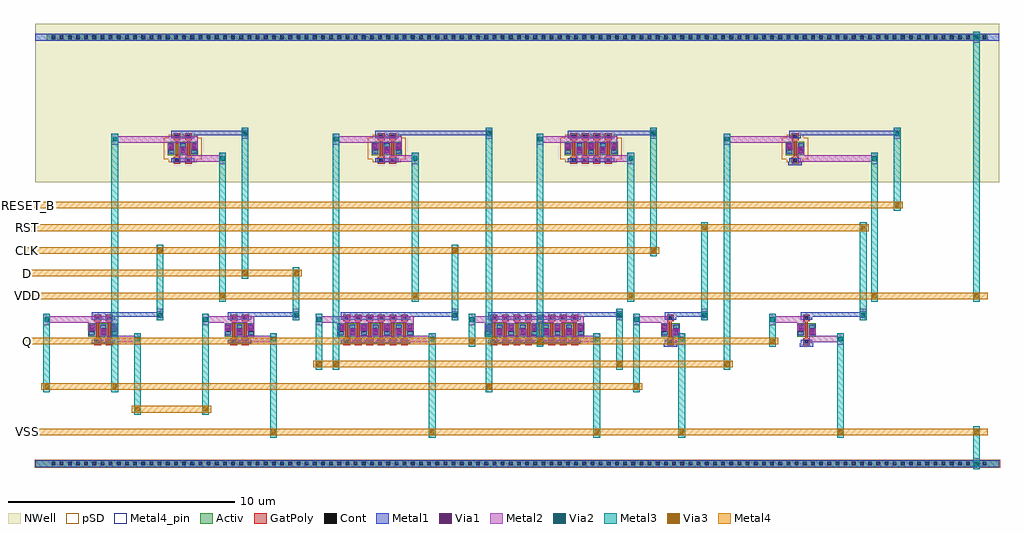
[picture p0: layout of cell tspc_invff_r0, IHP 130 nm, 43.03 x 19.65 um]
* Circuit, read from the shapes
.subckt tspc_invff_r0 CLK D Q RESET_B RST VDD VSS
XM1 dev_n_w0p6_l0p13_ng2_noguard_m1_2/D0 CLK dev_n_w0p6_l0p13_ng1_noguard_m1_7/D VSS sg13_lv_nmos w=0.6u l=0.13u m=2
XM2 VSS D dev_n_w0p6_l0p13_ng2_noguard_m1_2/D0 VSS sg13_lv_nmos w=0.6u l=0.13u m=2
XM3 VSS CLK dev_p_w0p6_l0p13_ng1_noguard_m1_8/D VSS sg13_lv_nmos w=0.6u l=0.13u m=6
XM4 VSS dev_p_w0p6_l0p13_ng1_noguard_m1_8/D Q VSS sg13_lv_nmos w=0.6u l=0.13u m=8
XM5 VSS RST dev_n_w0p6_l0p13_ng1_noguard_m1_7/D VSS sg13_lv_nmos w=0.6u l=0.13u
XM6 VSS RST Q VSS sg13_lv_nmos w=0.6u l=0.13u
XM7 VDD D dev_n_w0p6_l0p13_ng1_noguard_m1_7/D VDD sg13_lv_pmos w=0.6u l=0.13u m=2
XM8 VDD dev_n_w0p6_l0p13_ng1_noguard_m1_7/D dev_p_w0p6_l0p13_ng1_noguard_m1_8/D VDD sg13_lv_pmos w=0.6u l=0.13u m=2
XM9 VDD CLK Q VDD sg13_lv_pmos w=0.6u l=0.13u m=4
XM10 VDD RESET_B dev_p_w0p6_l0p13_ng1_noguard_m1_8/D VDD sg13_lv_pmos w=0.6u l=0.13u
.ends

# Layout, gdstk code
import gdstk
lib = gdstk.Library(unit=1e-6, precision=1e-09)
def R(c, l, rs):  # rectangles x0, y0, x1, y1
    for r in rs: c.add(gdstk.rectangle(r[:2], r[2:], *l))
def A(c, l, x, y, w, h, nx, ny, dx, dy):  # array of equal rectangles
    R(c, l, [(x+i*dx, y+j*dy, x+i*dx+w, y+j*dy+h) for i in range(nx) for j in range(ny)])
Activ = (1, 0)
GatPoly = (5, 0)
Cont = (6, 0)
Metal1 = (8, 0)
Metal2 = (10, 0)
pSD = (14, 0)
Via1 = (19, 0)
Via2 = (29, 0)
Metal3 = (30, 0)
NWell = (31, 0)
Via3 = (49, 0)
Metal4 = (50, 0)
Metal4_pin = (50, 2)

dev_n_w0p6_l0p13_ng2_nog = lib.new_cell('dev_n_w0p6_l0p13_ng2_noguard_m1')
R(dev_n_w0p6_l0p13_ng2_nog, Activ, [(-0.66,-0.3,0.66,0.3)])
R(dev_n_w0p6_l0p13_ng2_nog, GatPoly, [(-0.405,-0.67,-0.105,-0.37), (0.105,-0.67,0.405,-0.37), (-0.32,-0.37,-0.19,0.37), (0.19,-0.37,0.32,0.37), (-0.405,0.37,-0.105,0.67), (0.105,0.37,0.405,0.67)])
A(dev_n_w0p6_l0p13_ng2_nog, Cont, -0.59, -0.08, 0.16, 0.16, 3, 1, 0.51, 0)
R(dev_n_w0p6_l0p13_ng2_nog, Cont, [(-0.335,-0.6,-0.175,-0.44), (0.175,-0.6,0.335,-0.44), (-0.335,0.44,-0.175,0.6), (0.175,0.44,0.335,0.6)])
A(dev_n_w0p6_l0p13_ng2_nog, Metal1, -0.64, -0.23, 0.26, 0.46, 3, 1, 0.51, 0)
R(dev_n_w0p6_l0p13_ng2_nog, Metal1, [(-0.51,-0.6,0.51,-0.44), (-0.51,0.44,0.51,0.6)])
dev_n_w0p6_l0p13_ng2_nog.add(gdstk.Label('D0', (-0.51,0), layer=8, texttype=25))
dev_n_w0p6_l0p13_ng2_nog.add(gdstk.Label('G', (0.255,0.52), layer=8, texttype=25))
dev_n_w0p6_l0p13_ng2_nog.add(gdstk.Label('G', (-0.255,0.52), layer=8, texttype=25))
dev_n_w0p6_l0p13_ng2_nog.add(gdstk.Label('S1', (0,0), layer=8, texttype=25))

dev_p_w0p6_l0p13_ng2_nog = lib.new_cell('dev_p_w0p6_l0p13_ng2_noguard_m1')
R(dev_p_w0p6_l0p13_ng2_nog, Activ, [(-0.66,-0.3,0.66,0.3)])
R(dev_p_w0p6_l0p13_ng2_nog, GatPoly, [(-0.405,-0.67,-0.105,-0.37), (0.105,-0.67,0.405,-0.37), (-0.32,-0.37,-0.19,0.37), (0.19,-0.37,0.32,0.37), (-0.405,0.37,-0.105,0.67), (0.105,0.37,0.405,0.67)])
A(dev_p_w0p6_l0p13_ng2_nog, Cont, -0.59, -0.08, 0.16, 0.16, 3, 1, 0.51, 0)
R(dev_p_w0p6_l0p13_ng2_nog, Cont, [(-0.335,-0.6,-0.175,-0.44), (0.175,-0.6,0.335,-0.44), (-0.335,0.44,-0.175,0.6), (0.175,0.44,0.335,0.6)])
A(dev_p_w0p6_l0p13_ng2_nog, Metal1, -0.64, -0.23, 0.26, 0.46, 3, 1, 0.51, 0)
R(dev_p_w0p6_l0p13_ng2_nog, Metal1, [(-0.51,-0.6,0.51,-0.44), (-0.51,0.44,0.51,0.6)])
R(dev_p_w0p6_l0p13_ng2_nog, pSD, [(-0.62,-0.6,0.62,-0.48), (-0.84,-0.48,0.84,0.48), (-0.62,0.48,0.62,0.6)])
R(dev_p_w0p6_l0p13_ng2_nog, NWell, [(-0.97,-0.61,0.97,0.61)])
dev_p_w0p6_l0p13_ng2_nog.add(gdstk.Label('D0', (-0.51,0), layer=8, texttype=25))
dev_p_w0p6_l0p13_ng2_nog.add(gdstk.Label('G', (0.255,0.52), layer=8, texttype=25))
dev_p_w0p6_l0p13_ng2_nog.add(gdstk.Label('G', (-0.255,0.52), layer=8, texttype=25))
dev_p_w0p6_l0p13_ng2_nog.add(gdstk.Label('S1', (0,0), layer=8, texttype=25))

dev_n_w0p6_l0p13_ng6_nog = lib.new_cell('dev_n_w0p6_l0p13_ng6_noguard_m1')
R(dev_n_w0p6_l0p13_ng6_nog, Activ, [(-1.68,-0.3,1.68,0.3)])
A(dev_n_w0p6_l0p13_ng6_nog, GatPoly, -1.425, -0.67, 0.3, 0.3, 6, 2, 0.51, 1.04)
A(dev_n_w0p6_l0p13_ng6_nog, GatPoly, -1.34, -0.37, 0.13, 0.74, 6, 1, 0.51, 0)
A(dev_n_w0p6_l0p13_ng6_nog, Cont, -1.355, -0.6, 0.16, 0.16, 6, 2, 0.51, 1.04)
A(dev_n_w0p6_l0p13_ng6_nog, Cont, -1.61, -0.08, 0.16, 0.16, 7, 1, 0.51, 0)
A(dev_n_w0p6_l0p13_ng6_nog, Metal1, -1.66, -0.23, 0.26, 0.46, 7, 1, 0.51, 0)
R(dev_n_w0p6_l0p13_ng6_nog, Metal1, [(-1.53,-0.6,1.53,-0.44), (-1.53,0.44,1.53,0.6)])
dev_n_w0p6_l0p13_ng6_nog.add(gdstk.Label('D0', (-1.53,0), layer=8, texttype=25))
dev_n_w0p6_l0p13_ng6_nog.add(gdstk.Label('G', (1.275,0.52), layer=8, texttype=25))
dev_n_w0p6_l0p13_ng6_nog.add(gdstk.Label('G', (0.765,0.52), layer=8, texttype=25))
dev_n_w0p6_l0p13_ng6_nog.add(gdstk.Label('G', (0.255,0.52), layer=8, texttype=25))
dev_n_w0p6_l0p13_ng6_nog.add(gdstk.Label('G', (-0.255,0.52), layer=8, texttype=25))
dev_n_w0p6_l0p13_ng6_nog.add(gdstk.Label('G', (-0.765,0.52), layer=8, texttype=25))
dev_n_w0p6_l0p13_ng6_nog.add(gdstk.Label('G', (-1.275,0.52), layer=8, texttype=25))
dev_n_w0p6_l0p13_ng6_nog.add(gdstk.Label('S1', (-1.02,0), layer=8, texttype=25))
dev_n_w0p6_l0p13_ng6_nog.add(gdstk.Label('D2', (-0.51,0), layer=8, texttype=25))
dev_n_w0p6_l0p13_ng6_nog.add(gdstk.Label('S3', (0,0), layer=8, texttype=25))
dev_n_w0p6_l0p13_ng6_nog.add(gdstk.Label('D4', (0.51,0), layer=8, texttype=25))
dev_n_w0p6_l0p13_ng6_nog.add(gdstk.Label('S5', (1.02,0), layer=8, texttype=25))

dev_n_w0p6_l0p13_ng8_nog = lib.new_cell('dev_n_w0p6_l0p13_ng8_noguard_m1')
R(dev_n_w0p6_l0p13_ng8_nog, Activ, [(-2.19,-0.3,2.19,0.3)])
A(dev_n_w0p6_l0p13_ng8_nog, GatPoly, -1.935, -0.67, 0.3, 0.3, 8, 2, 0.51, 1.04)
A(dev_n_w0p6_l0p13_ng8_nog, GatPoly, -1.85, -0.37, 0.13, 0.74, 8, 1, 0.51, 0)
A(dev_n_w0p6_l0p13_ng8_nog, Cont, -1.865, -0.6, 0.16, 0.16, 8, 2, 0.51, 1.04)
A(dev_n_w0p6_l0p13_ng8_nog, Cont, -2.12, -0.08, 0.16, 0.16, 9, 1, 0.51, 0)
A(dev_n_w0p6_l0p13_ng8_nog, Metal1, -2.17, -0.23, 0.26, 0.46, 9, 1, 0.51, 0)
R(dev_n_w0p6_l0p13_ng8_nog, Metal1, [(-2.04,-0.6,2.04,-0.44), (-2.04,0.44,2.04,0.6)])
dev_n_w0p6_l0p13_ng8_nog.add(gdstk.Label('D0', (-2.04,0), layer=8, texttype=25))
dev_n_w0p6_l0p13_ng8_nog.add(gdstk.Label('G', (1.785,0.52), layer=8, texttype=25))
dev_n_w0p6_l0p13_ng8_nog.add(gdstk.Label('G', (1.275,0.52), layer=8, texttype=25))
dev_n_w0p6_l0p13_ng8_nog.add(gdstk.Label('G', (0.765,0.52), layer=8, texttype=25))
dev_n_w0p6_l0p13_ng8_nog.add(gdstk.Label('G', (0.255,0.52), layer=8, texttype=25))
dev_n_w0p6_l0p13_ng8_nog.add(gdstk.Label('G', (-0.255,0.52), layer=8, texttype=25))
dev_n_w0p6_l0p13_ng8_nog.add(gdstk.Label('G', (-0.765,0.52), layer=8, texttype=25))
dev_n_w0p6_l0p13_ng8_nog.add(gdstk.Label('G', (-1.275,0.52), layer=8, texttype=25))
dev_n_w0p6_l0p13_ng8_nog.add(gdstk.Label('G', (-1.785,0.52), layer=8, texttype=25))
dev_n_w0p6_l0p13_ng8_nog.add(gdstk.Label('S1', (-1.53,0), layer=8, texttype=25))
dev_n_w0p6_l0p13_ng8_nog.add(gdstk.Label('D2', (-1.02,0), layer=8, texttype=25))
dev_n_w0p6_l0p13_ng8_nog.add(gdstk.Label('S3', (-0.51,0), layer=8, texttype=25))
dev_n_w0p6_l0p13_ng8_nog.add(gdstk.Label('D4', (0,0), layer=8, texttype=25))
dev_n_w0p6_l0p13_ng8_nog.add(gdstk.Label('S5', (0.51,0), layer=8, texttype=25))
dev_n_w0p6_l0p13_ng8_nog.add(gdstk.Label('D6', (1.02,0), layer=8, texttype=25))
dev_n_w0p6_l0p13_ng8_nog.add(gdstk.Label('S7', (1.53,0), layer=8, texttype=25))

dev_p_w0p6_l0p13_ng4_nog = lib.new_cell('dev_p_w0p6_l0p13_ng4_noguard_m1')
R(dev_p_w0p6_l0p13_ng4_nog, Activ, [(-1.17,-0.3,1.17,0.3)])
A(dev_p_w0p6_l0p13_ng4_nog, GatPoly, -0.915, -0.67, 0.3, 0.3, 4, 2, 0.51, 1.04)
A(dev_p_w0p6_l0p13_ng4_nog, GatPoly, -0.83, -0.37, 0.13, 0.74, 4, 1, 0.51, 0)
A(dev_p_w0p6_l0p13_ng4_nog, Cont, -0.845, -0.6, 0.16, 0.16, 4, 2, 0.51, 1.04)
A(dev_p_w0p6_l0p13_ng4_nog, Cont, -1.1, -0.08, 0.16, 0.16, 5, 1, 0.51, 0)
A(dev_p_w0p6_l0p13_ng4_nog, Metal1, -1.15, -0.23, 0.26, 0.46, 5, 1, 0.51, 0)
R(dev_p_w0p6_l0p13_ng4_nog, Metal1, [(-1.02,-0.6,1.02,-0.44), (-1.02,0.44,1.02,0.6)])
R(dev_p_w0p6_l0p13_ng4_nog, pSD, [(-1.13,-0.6,1.13,-0.48), (-1.35,-0.48,1.35,0.48), (-1.13,0.48,1.13,0.6)])
R(dev_p_w0p6_l0p13_ng4_nog, NWell, [(-1.48,-0.61,1.48,0.61)])
dev_p_w0p6_l0p13_ng4_nog.add(gdstk.Label('D0', (-1.02,0), layer=8, texttype=25))
dev_p_w0p6_l0p13_ng4_nog.add(gdstk.Label('G', (0.765,0.52), layer=8, texttype=25))
dev_p_w0p6_l0p13_ng4_nog.add(gdstk.Label('G', (0.255,0.52), layer=8, texttype=25))
dev_p_w0p6_l0p13_ng4_nog.add(gdstk.Label('G', (-0.255,0.52), layer=8, texttype=25))
dev_p_w0p6_l0p13_ng4_nog.add(gdstk.Label('G', (-0.765,0.52), layer=8, texttype=25))
dev_p_w0p6_l0p13_ng4_nog.add(gdstk.Label('S1', (-0.51,0), layer=8, texttype=25))
dev_p_w0p6_l0p13_ng4_nog.add(gdstk.Label('D2', (0,0), layer=8, texttype=25))
dev_p_w0p6_l0p13_ng4_nog.add(gdstk.Label('S3', (0.51,0), layer=8, texttype=25))

dev_n_w0p6_l0p13_ng1_nog = lib.new_cell('dev_n_w0p6_l0p13_ng1_noguard_m1')
R(dev_n_w0p6_l0p13_ng1_nog, Activ, [(-0.405,-0.3,0.405,0.3)])
R(dev_n_w0p6_l0p13_ng1_nog, GatPoly, [(-0.15,-0.67,0.15,-0.37), (-0.065,-0.37,0.065,0.37), (-0.15,0.37,0.15,0.67)])
R(dev_n_w0p6_l0p13_ng1_nog, Cont, [(-0.08,-0.6,0.08,-0.44), (-0.335,-0.08,-0.175,0.08), (0.175,-0.08,0.335,0.08), (-0.08,0.44,0.08,0.6)])
R(dev_n_w0p6_l0p13_ng1_nog, Metal1, [(-0.255,-0.6,0.255,-0.44), (-0.385,-0.23,-0.125,0.23), (0.125,-0.23,0.385,0.23), (-0.255,0.44,0.255,0.6)])
dev_n_w0p6_l0p13_ng1_nog.add(gdstk.Label('D', (-0.255,0), layer=8, texttype=25))
dev_n_w0p6_l0p13_ng1_nog.add(gdstk.Label('S', (0.255,0), layer=8, texttype=25))
dev_n_w0p6_l0p13_ng1_nog.add(gdstk.Label('G', (0,0.52), layer=8, texttype=25))

dev_p_w0p6_l0p13_ng1_nog = lib.new_cell('dev_p_w0p6_l0p13_ng1_noguard_m1')
R(dev_p_w0p6_l0p13_ng1_nog, Activ, [(-0.405,-0.3,0.405,0.3)])
R(dev_p_w0p6_l0p13_ng1_nog, GatPoly, [(-0.15,-0.67,0.15,-0.37), (-0.065,-0.37,0.065,0.37), (-0.15,0.37,0.15,0.67)])
R(dev_p_w0p6_l0p13_ng1_nog, Cont, [(-0.08,-0.6,0.08,-0.44), (-0.335,-0.08,-0.175,0.08), (0.175,-0.08,0.335,0.08), (-0.08,0.44,0.08,0.6)])
R(dev_p_w0p6_l0p13_ng1_nog, Metal1, [(-0.255,-0.6,0.255,-0.44), (-0.385,-0.23,-0.125,0.23), (0.125,-0.23,0.385,0.23), (-0.255,0.44,0.255,0.6)])
R(dev_p_w0p6_l0p13_ng1_nog, pSD, [(-0.365,-0.6,0.365,-0.48), (-0.585,-0.48,0.585,0.48), (-0.365,0.48,0.365,0.6)])
R(dev_p_w0p6_l0p13_ng1_nog, NWell, [(-0.715,-0.61,0.715,0.61)])
dev_p_w0p6_l0p13_ng1_nog.add(gdstk.Label('D', (-0.255,0), layer=8, texttype=25))
dev_p_w0p6_l0p13_ng1_nog.add(gdstk.Label('S', (0.255,0), layer=8, texttype=25))
dev_p_w0p6_l0p13_ng1_nog.add(gdstk.Label('G', (0,0.52), layer=8, texttype=25))

tspc_invff_r0 = lib.new_cell('tspc_invff_r0')
R(tspc_invff_r0, Activ, [(-3,-6.05,39.5,-5.75), (-2.5,12.75,39,13.05)])
A(tspc_invff_r0, Cont, -2.28, -5.98, 0.16, 0.16, 115, 2, 0.36, 18.8)
A(tspc_invff_r0, Metal1, 10.835, -0.245, 0.29, 0.29, 3, 1, 1.02, 0)
A(tspc_invff_r0, Metal1, 17.325, -0.245, 0.29, 0.29, 4, 1, 1.02, 0)
A(tspc_invff_r0, Metal1, 10.325, -0.045, 0.29, 0.29, 4, 1, 1.02, 0)
A(tspc_invff_r0, Metal1, 16.815, -0.045, 0.29, 0.29, 5, 1, 1.02, 0)
A(tspc_invff_r0, Metal1, 20.335, 7.955, 0.29, 0.29, 3, 1, 1.02, 0)
R(tspc_invff_r0, Metal1, [(-3,-6.05,39.5,-5.75), (24.7,-0.75,25.3,-0.59), (30.7,-0.75,31.3,-0.59), (-0.145,-0.245,0.145,0.045), (5.855,-0.245,6.145,0.045), (25.11,-0.245,25.4,0.045), (31.11,-0.245,31.4,0.045), (-0.655,-0.045,-0.365,0.245), (0.365,-0.045,0.655,0.245), (5.345,-0.045,5.635,0.245), (6.365,-0.045,6.655,0.245), (24.6,-0.045,24.89,0.245), (30.6,-0.045,30.89,0.245), (2.355,0.525,2.645,0.57), (8.355,0.525,8.645,0.57), (15.355,0.525,15.645,0.57), (22.605,0.525,22.895,0.57), (26.355,0.525,26.645,0.57), (33.355,0.525,33.645,0.57), (-0.51,0.57,2.645,0.78), (5.49,0.57,8.645,0.78), (10.47,0.57,15.645,0.78), (16.96,0.57,22.895,0.78), (24.745,0.57,26.645,0.78), (30.745,0.57,33.645,0.78), (2.355,0.78,2.645,0.815), (8.355,0.78,8.645,0.815), (15.355,0.78,15.645,0.815), (22.605,0.78,22.895,0.815), (26.355,0.78,26.645,0.815), (33.355,0.78,33.645,0.815), (30.2,7.25,30.8,7.41), (3.355,7.755,3.645,8.045), (12.355,7.755,12.645,8.045), (20.845,7.755,21.135,8.045), (21.865,7.755,22.155,8.045), (30.61,7.755,30.9,8.045), (2.845,7.955,3.135,8.245), (3.865,7.955,4.155,8.245), (11.845,7.955,12.135,8.245), (12.865,7.955,13.155,8.245), (30.1,7.955,30.39,8.245), (6.105,8.525,6.395,8.57), (16.855,8.525,17.145,8.57), (24.105,8.525,24.395,8.57), (34.855,8.525,35.145,8.57), (2.99,8.57,6.395,8.78), (11.99,8.57,17.145,8.78), (20.48,8.57,24.395,8.78), (30.245,8.57,35.145,8.78), (6.105,8.78,6.395,8.815), (16.855,8.78,17.145,8.815), (24.105,8.78,24.395,8.815), (34.855,8.78,35.145,8.815), (-3,12.75,39.5,13.05)])
A(tspc_invff_r0, Metal2, 10.835, -0.255, 0.29, 0.3, 3, 1, 1.02, 0)
A(tspc_invff_r0, Metal2, 17.325, -0.255, 0.29, 0.3, 4, 1, 1.02, 0)
A(tspc_invff_r0, Metal2, 10.325, -0.045, 0.29, 0.35, 4, 1, 1.02, 0)
A(tspc_invff_r0, Metal2, 16.815, -0.045, 0.29, 0.35, 5, 1, 1.02, 0)
A(tspc_invff_r0, Metal2, 20.335, 7.955, 0.29, 0.3, 3, 1, 1.02, 0)
R(tspc_invff_r0, Metal2, [(38.355,-6.15,38.645,-5.65), (1.355,-0.65,1.645,-0.545), (7.355,-0.65,7.645,-0.545), (14.355,-0.65,14.645,-0.545), (21.605,-0.65,21.895,-0.545), (25.355,-0.65,25.645,-0.545), (32.355,-0.65,32.645,-0.545), (-0.145,-0.545,1.645,-0.255), (5.855,-0.545,7.645,-0.255), (10.835,-0.545,14.645,-0.255), (17.325,-0.545,21.895,-0.255), (25.11,-0.545,25.645,-0.15), (31.11,-0.545,32.645,-0.255), (-0.145,-0.255,0.145,0.045), (1.355,-0.255,1.645,-0.15), (5.855,-0.255,6.145,0.045), (7.355,-0.255,7.645,-0.15), (14.355,-0.255,14.645,-0.15), (21.605,-0.255,21.895,-0.15), (31.11,-0.255,31.4,0.045), (32.355,-0.255,32.645,-0.15), (25.11,-0.15,25.4,0.045), (-0.655,-0.045,-0.365,0.305), (0.365,-0.045,0.655,0.305), (5.345,-0.045,5.635,0.305), (6.365,-0.045,6.655,0.305), (24.6,-0.045,24.89,0.305), (30.6,-0.045,30.89,0.305), (-2.645,0.2,-2.355,0.305), (4.355,0.2,4.645,0.305), (9.355,0.2,9.645,0.305), (16.105,0.2,16.395,0.305), (23.355,0.2,23.645,0.305), (29.355,0.2,29.645,0.305), (-2.645,0.305,0.655,0.595), (4.355,0.305,6.655,0.595), (9.355,0.305,13.675,0.595), (16.105,0.305,21.185,0.595), (23.355,0.305,24.89,0.595), (29.355,0.305,30.89,0.595), (2.355,0.42,2.645,0.92), (8.355,0.42,8.645,0.92), (15.355,0.42,15.645,0.92), (22.605,0.42,22.895,0.92), (26.355,0.42,26.645,0.92), (33.355,0.42,33.645,0.92), (-2.645,0.595,-2.355,0.7), (4.355,0.595,4.645,0.7), (9.355,0.595,9.645,0.7), (16.105,0.595,16.395,0.7), (23.355,0.595,23.645,0.7), (29.355,0.595,29.645,0.7), (5.105,7.3,5.395,7.405), (13.605,7.3,13.895,7.405), (23.105,7.3,23.395,7.405), (33.855,7.3,34.145,7.405), (3.355,7.405,5.395,7.695), (12.355,7.405,13.895,7.695), (20.845,7.405,23.395,7.695), (30.61,7.405,34.145,7.695), (3.355,7.695,3.645,8.045), (5.105,7.695,5.395,7.8), (12.355,7.695,12.645,8.045), (13.605,7.695,13.895,7.8), (20.845,7.695,21.135,8.045), (21.865,7.695,22.155,8.045), (23.105,7.695,23.395,7.8), (30.61,7.695,30.9,8.045), (33.855,7.695,34.145,7.8), (2.845,7.955,3.135,8.255), (3.865,7.955,4.155,8.255), (11.845,7.955,12.135,8.255), (12.865,7.955,13.155,8.255), (30.1,7.955,30.39,8.255), (0.355,8.15,0.645,8.255), (10.105,8.15,10.395,8.255), (19.105,8.15,19.395,8.255), (27.355,8.15,27.645,8.255), (0.355,8.255,4.155,8.545), (10.105,8.255,13.155,8.545), (19.105,8.255,22.665,8.545), (27.355,8.255,30.39,8.545), (6.105,8.42,6.395,8.92), (16.855,8.42,17.145,8.92), (24.105,8.42,24.395,8.92), (34.855,8.42,35.145,8.92), (0.355,8.545,0.645,8.65), (10.105,8.545,10.395,8.65), (19.105,8.545,19.395,8.65), (27.355,8.545,27.645,8.65), (38.355,12.65,38.645,13.15)])
R(tspc_invff_r0, pSD, [(-3.03,-6.08,39.53,-5.72)])
A(tspc_invff_r0, Via1, 10.885, -0.195, 0.19, 0.19, 3, 1, 1.02, 0)
A(tspc_invff_r0, Via1, 17.375, -0.195, 0.19, 0.19, 4, 1, 1.02, 0)
A(tspc_invff_r0, Via1, 10.375, 0.005, 0.19, 0.19, 4, 1, 1.02, 0)
A(tspc_invff_r0, Via1, 16.865, 0.005, 0.19, 0.19, 5, 1, 1.02, 0)
A(tspc_invff_r0, Via1, 20.385, 8.005, 0.19, 0.19, 3, 1, 1.02, 0)
R(tspc_invff_r0, Via1, [(38.405,-5.995,38.595,-5.805), (-0.095,-0.195,0.095,-0.005), (5.905,-0.195,6.095,-0.005), (25.16,-0.195,25.35,-0.005), (31.16,-0.195,31.35,-0.005), (-0.605,0.005,-0.415,0.195), (0.415,0.005,0.605,0.195), (5.395,0.005,5.585,0.195), (6.415,0.005,6.605,0.195), (24.65,0.005,24.84,0.195), (30.65,0.005,30.84,0.195), (2.405,0.575,2.595,0.765), (8.405,0.575,8.595,0.765), (15.405,0.575,15.595,0.765), (22.655,0.575,22.845,0.765), (26.405,0.575,26.595,0.765), (33.405,0.575,33.595,0.765), (3.405,7.805,3.595,7.995), (12.405,7.805,12.595,7.995), (20.895,7.805,21.085,7.995), (21.915,7.805,22.105,7.995), (30.66,7.805,30.85,7.995), (2.895,8.005,3.085,8.195), (3.915,8.005,4.105,8.195), (11.895,8.005,12.085,8.195), (12.915,8.005,13.105,8.195), (30.15,8.005,30.34,8.195), (6.155,8.575,6.345,8.765), (16.905,8.575,17.095,8.765), (24.155,8.575,24.345,8.765), (34.905,8.575,35.095,8.765), (38.405,12.805,38.595,12.995)])
R(tspc_invff_r0, Via2, [(38.405,-5.995,38.595,-5.805), (1.405,-0.495,1.595,-0.305), (7.405,-0.495,7.595,-0.305), (14.405,-0.495,14.595,-0.305), (21.655,-0.495,21.845,-0.305), (25.405,-0.495,25.595,-0.305), (32.405,-0.495,32.595,-0.305), (-2.595,0.355,-2.405,0.545), (4.405,0.355,4.595,0.545), (9.405,0.355,9.595,0.545), (16.155,0.355,16.345,0.545), (23.405,0.355,23.595,0.545), (29.405,0.355,29.595,0.545), (2.405,0.575,2.595,0.765), (8.405,0.575,8.595,0.765), (15.405,0.575,15.595,0.765), (22.655,0.575,22.845,0.765), (26.405,0.575,26.595,0.765), (33.405,0.575,33.595,0.765), (5.155,7.455,5.345,7.645), (13.655,7.455,13.845,7.645), (23.155,7.455,23.345,7.645), (33.905,7.455,34.095,7.645), (0.405,8.305,0.595,8.495), (10.155,8.305,10.345,8.495), (19.155,8.305,19.345,8.495), (27.405,8.305,27.595,8.495), (6.155,8.575,6.345,8.765), (16.905,8.575,17.095,8.765), (24.155,8.575,24.345,8.765), (34.905,8.575,35.095,8.765), (38.405,12.805,38.595,12.995)])
R(tspc_invff_r0, Metal3, [(38.355,-6.15,38.645,-4.25), (7.355,-4.75,7.645,-0.15), (14.355,-4.75,14.645,-0.15), (21.605,-4.75,21.895,-0.15), (25.355,-4.75,25.645,-0.15), (32.355,-4.75,32.645,-0.15), (1.355,-3.75,1.645,-0.15), (4.355,-3.75,4.645,0.7), (-2.645,-2.75,-2.355,0.7), (0.355,-2.75,0.645,8.65), (16.855,-2.75,17.145,8.92), (23.355,-2.75,23.645,0.7), (9.355,-1.75,9.645,0.7), (10.105,-1.75,10.395,8.65), (22.605,-1.75,22.895,0.92), (27.355,-1.75,27.645,8.65), (16.105,-0.75,16.395,0.7), (19.105,-0.75,19.395,8.65), (29.355,-0.75,29.645,0.7), (2.355,0.42,2.645,3.75), (8.355,0.42,8.645,2.75), (15.355,0.42,15.645,3.75), (26.355,0.42,26.645,4.75), (33.355,0.42,33.645,4.75), (5.105,1.25,5.395,7.8), (13.605,1.25,13.895,7.8), (23.105,1.25,23.395,7.8), (33.855,1.25,34.145,7.8), (38.355,1.25,38.645,13.15), (6.105,2.25,6.395,8.92), (24.105,3.25,24.395,8.92), (34.855,5.25,35.145,8.92)])
R(tspc_invff_r0, NWell, [(-3,6.5,39.5,13.5)])
R(tspc_invff_r0, Via3, [(7.405,-4.595,7.595,-4.405), (14.405,-4.595,14.595,-4.405), (21.655,-4.595,21.845,-4.405), (25.405,-4.595,25.595,-4.405), (32.405,-4.595,32.595,-4.405), (38.405,-4.595,38.595,-4.405), (1.405,-3.595,1.595,-3.405), (4.405,-3.595,4.595,-3.405), (-2.595,-2.595,-2.405,-2.405), (0.405,-2.595,0.595,-2.405), (16.905,-2.595,17.095,-2.405), (23.405,-2.595,23.595,-2.405), (9.405,-1.595,9.595,-1.405), (10.155,-1.595,10.345,-1.405), (22.655,-1.595,22.845,-1.405), (27.405,-1.595,27.595,-1.405), (16.155,-0.595,16.345,-0.405), (19.155,-0.595,19.345,-0.405), (29.405,-0.595,29.595,-0.405), (5.155,1.405,5.345,1.595), (13.655,1.405,13.845,1.595), (23.155,1.405,23.345,1.595), (33.905,1.405,34.095,1.595), (38.405,1.405,38.595,1.595), (6.155,2.405,6.345,2.595), (8.405,2.405,8.595,2.595), (2.405,3.405,2.595,3.595), (15.405,3.405,15.595,3.595), (24.155,3.405,24.345,3.595), (26.405,4.405,26.595,4.595), (33.405,4.405,33.595,4.595), (34.905,5.405,35.095,5.595)])
R(tspc_invff_r0, Metal4, [(-3.5,-4.645,39,-4.355), (1.25,-3.645,4.75,-3.355), (-2.75,-2.645,23.75,-2.355), (9.25,-1.645,27.75,-1.355), (-3.5,-0.645,29.75,-0.355), (-3.5,1.355,39,1.645), (-3.5,2.355,8.75,2.645), (-3.5,3.355,24.5,3.645), (-3.5,4.355,33.75,4.645), (-3.5,5.355,35.25,5.645)])
A(tspc_invff_r0, Metal4_pin, -3.5, 1.355, 0.3, 0.29, 1, 5, 0, 1)
R(tspc_invff_r0, Metal4_pin, [(-3.5,-4.645,-3.2,-4.355), (-3.5,-0.645,-3.2,-0.355)])
tspc_invff_r0.add(gdstk.Reference(dev_n_w0p6_l0p13_ng2_nog, (0,0)))
tspc_invff_r0.add(gdstk.Reference(dev_p_w0p6_l0p13_ng2_nog, (3.5,8)))
tspc_invff_r0.add(gdstk.Reference(dev_n_w0p6_l0p13_ng2_nog, (6,0)))
tspc_invff_r0.add(gdstk.Reference(dev_n_w0p6_l0p13_ng6_nog, (12,0)))
tspc_invff_r0.add(gdstk.Reference(dev_p_w0p6_l0p13_ng2_nog, (12.5,8)))
tspc_invff_r0.add(gdstk.Reference(dev_n_w0p6_l0p13_ng8_nog, (19,0)))
tspc_invff_r0.add(gdstk.Reference(dev_p_w0p6_l0p13_ng4_nog, (21.5,8)))
tspc_invff_r0.add(gdstk.Reference(dev_n_w0p6_l0p13_ng1_nog, (25,0)))
tspc_invff_r0.add(gdstk.Reference(dev_p_w0p6_l0p13_ng1_nog, (30.5,8)))
tspc_invff_r0.add(gdstk.Reference(dev_n_w0p6_l0p13_ng1_nog, (31,0)))
tspc_invff_r0.add(gdstk.Label('D', (-3.35,2.5), layer=50, texttype=25))
tspc_invff_r0.add(gdstk.Label('CLK', (-3.35,3.5), layer=50, texttype=25))
tspc_invff_r0.add(gdstk.Label('Q', (-3.35,-0.5), layer=50, texttype=25))
tspc_invff_r0.add(gdstk.Label('RST', (-3.35,4.5), layer=50, texttype=25))
tspc_invff_r0.add(gdstk.Label('RESET_B', (-3.35,5.5), layer=50, texttype=25))
tspc_invff_r0.add(gdstk.Label('VDD', (-3.35,1.5), layer=50, texttype=25))
tspc_invff_r0.add(gdstk.Label('VSS', (-3.35,-4.5), layer=50, texttype=25))

lib.write_gds('tspc_invff_r0.gds')
